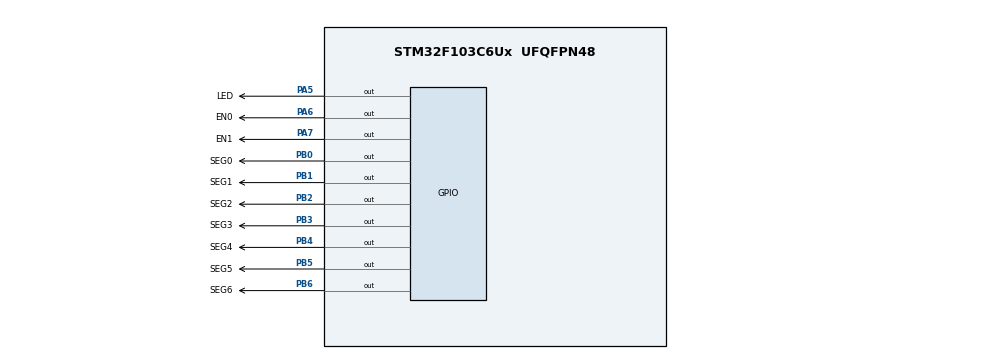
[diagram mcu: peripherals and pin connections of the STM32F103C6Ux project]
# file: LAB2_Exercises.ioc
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Mcu.Family=STM32F1
Mcu.Name=STM32F103C6Ux
Mcu.Package=UFQFPN48
NVIC.PriorityGroup=NVIC_PRIORITYGROUP_4
NVIC.TIM2_IRQn=true\:0\:0\:false\:false\:true\:true\:true
PA5.GPIO_Label=LED
PA5.Signal=GPIO_Output
PA6.GPIO_Label=EN0
PA6.Signal=GPIO_Output
PA7.GPIO_Label=EN1
PA7.Signal=GPIO_Output
PB0.GPIO_Label=SEG0
PB0.Signal=GPIO_Output
PB1.GPIO_Label=SEG1
PB1.Signal=GPIO_Output
PB2.GPIO_Label=SEG2
PB2.Signal=GPIO_Output
PB3.GPIO_Label=SEG3
PB3.Signal=GPIO_Output
PB4.GPIO_Label=SEG4
PB4.Signal=GPIO_Output
PB5.GPIO_Label=SEG5
PB5.Signal=GPIO_Output
PB6.GPIO_Label=SEG6
PB6.Signal=GPIO_Output
ProjectManager.HeapSize=0x200
ProjectManager.StackSize=0x400
ProjectManager.TargetToolchain=STM32CubeIDE
RCC.APB1Freq_Value=8000000
RCC.APB2Freq_Value=8000000
TIM2.Period=9
TIM2.Prescaler=7999
VP_SYS_VS_ND.Mode=No_Debug
VP_TIM2_VS_ClockSourceINT.Mode=Internal
board=custom

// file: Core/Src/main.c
	/* USER CODE BEGIN Header */
/**
  ******************************************************************************
  * @file           : main.c
  * @brief          : Main program body
  ******************************************************************************
  * @attention
  *
  * <h2><center>&copy; Copyright (c) 2023 STMicroelectronics.
  * All rights reserved.</center></h2>
  *
  * This software component is licensed by ST under BSD 3-Clause license,
  * the "License"; You may not use this file except in compliance with the
  * License. You may obtain a copy of the License at:
  *                        opensource.org/licenses/BSD-3-Clause
  *
  ******************************************************************************
  */
/* USER CODE END Header */
#include "main.h"
// Idea : Split the hexadecimal number into corresponding bits for display
void displayDOT ( uint8_t num ) {
	HAL_GPIO_WritePin(ENM0_GPIO_Port, ENM7_Pin, !( num & 0x01 ));
	HAL_GPIO_WritePin(ENM1_GPIO_Port, ENM6_Pin, !( num & 0x02 ));
	HAL_GPIO_WritePin(ENM2_GPIO_Port, ENM5_Pin, !( num & 0x04 ));
	HAL_GPIO_WritePin(ENM3_GPIO_Port, ENM4_Pin, !( num & 0x08 ));
	HAL_GPIO_WritePin(ENM4_GPIO_Port, ENM3_Pin, !( num & 0x10 ));
	HAL_GPIO_WritePin(ENM5_GPIO_Port, ENM2_Pin, !( num & 0x20 ));
	HAL_GPIO_WritePin(ENM6_GPIO_Port, ENM1_Pin, !( num & 0x40 ));
	HAL_GPIO_WritePin(ENM7_GPIO_Port, ENM0_Pin, !( num & 0x80 ));
}

// Idea : For the first time running , turn off all the LEDs for easy display
void clearMatrix () {
	HAL_GPIO_WritePin(ROW0_GPIO_Port, ROW0_Pin, 1);
	HAL_GPIO_WritePin(ROW1_GPIO_Port, ROW1_Pin, 1);
	HAL_GPIO_WritePin(ROW2_GPIO_Port, ROW2_Pin, 1);
	HAL_GPIO_WritePin(ROW3_GPIO_Port, ROW3_Pin, 1);
	HAL_GPIO_WritePin(ROW4_GPIO_Port, ROW4_Pin, 1);
	HAL_GPIO_WritePin(ROW5_GPIO_Port, ROW5_Pin, 1);
	HAL_GPIO_WritePin(ROW6_GPIO_Port, ROW6_Pin, 1);
	HAL_GPIO_WritePin(ROW7_GPIO_Port, ROW7_Pin, 1);
}

// Idea : Display the hexadecimal values in the corresponding row using led scanning
uint8_t matrix_buffer[8] = {0x18, 0x3c, 0x66, 0x7e, 0x66, 0x66, 0x66}; // Character A
void updateLEDMatrix (int index) {
	switch (index) {
	case 0:
		displayDOT(matrix_buffer[0]);
		HAL_GPIO_WritePin(ROW7_GPIO_Port, ROW7_Pin, 1);
		HAL_GPIO_WritePin(ROW0_GPIO_Port, ROW0_Pin, 0);
		break;
	case 1:
		displayDOT(matrix_buffer[1]);
		HAL_GPIO_WritePin(ROW0_GPIO_Port, ROW0_Pin, 1);
		HAL_GPIO_WritePin(ROW1_GPIO_Port, ROW1_Pin, 0);
		break;
	case 2:
		displayDOT(matrix_buffer[2]);
		HAL_GPIO_WritePin(ROW1_GPIO_Port, ROW1_Pin, 1);
		HAL_GPIO_WritePin(ROW2_GPIO_Port, ROW2_Pin, 0);
		break;
	case 3:
		displayDOT(matrix_buffer[3]);
		HAL_GPIO_WritePin(ROW2_GPIO_Port, ROW2_Pin, 1);
		HAL_GPIO_WritePin(ROW3_GPIO_Port, ROW3_Pin, 0);
		break;
	case 4:
		displayDOT(matrix_buffer[4]);
		HAL_GPIO_WritePin(ROW3_GPIO_Port, ROW3_Pin, 1);
		HAL_GPIO_WritePin(ROW4_GPIO_Port, ROW4_Pin, 0);
		break;
	case 5:
		displayDOT(matrix_buffer[5]);
		HAL_GPIO_WritePin(ROW4_GPIO_Port, ROW4_Pin, 1);
		HAL_GPIO_WritePin(ROW5_GPIO_Port, ROW5_Pin, 0);
		break;
	case 6:
		displayDOT(matrix_buffer[6]);
		HAL_GPIO_WritePin(ROW5_GPIO_Port, ROW5_Pin, 1);
		HAL_GPIO_WritePin(ROW6_GPIO_Port, ROW6_Pin, 0);
		break;
	case 7:
		displayDOT(matrix_buffer[7]);
		HAL_GPIO_WritePin(ROW6_GPIO_Port, ROW6_Pin, 1);
		HAL_GPIO_WritePin(ROW7_GPIO_Port, ROW7_Pin, 0);
		break;
	default:
		break;
	}
}

TIM_HandleTypeDef htim2;

void SystemClock_Config(void);
static void MX_GPIO_Init(void);
static void MX_TIM2_Init(void);

/* USER CODE BEGIN 0 */
// Idea: Use another software timer called timer1 for presenting 4  7-SEG LEDs.
// Use  setTimer1(250) and TIMER_CYCLE = 10, we have the timer1_counter = 25, therefore, the switching time between 7-SEG LEDS is 0.25s
int timer2_counter = 0;
int timer2_flag = 0;
int TIMER_CYCLE = 10;
void setTimer2 (int duration) {
	timer2_counter = duration / TIMER_CYCLE;
	timer2_flag = 0;
}
void timer_run () {
	if (timer2_counter > 0) {
		timer2_counter--;
		if (timer2_counter == 0) timer2_flag = 1;
	}
}
/* USER CODE END 0 */

int main(void)
{

  /* MCU Configuration--------------------------------------------------------*/

  /* Reset of all peripherals, Initializes the Flash interface and the Systick. */
  HAL_Init();

  /* Configure the system clock */
  SystemClock_Config();

  /* Initialize all configured peripherals */
  MX_GPIO_Init();
  MX_TIM2_Init();
  /* USER CODE BEGIN 2 */
  HAL_TIM_Base_Start_IT(&htim2);
  /* USER CODE END 2 */

  /* Infinite loop */
  /* USER CODE BEGIN WHILE */
  setTimer2(10);
  int index = 0;
  clearMatrix();
  while (1)
  {
	  if (timer2_flag == 1) {
		  setTimer2(40);
		  updateLEDMatrix(index++);
		  if (index > 7) {
			  index = 0;
		  }
	  }
  }
  /* USER CODE END 3 */
}

void SystemClock_Config(void)
{
  RCC_OscInitTypeDef RCC_OscInitStruct = {0};
  RCC_ClkInitTypeDef RCC_ClkInitStruct = {0};

  /** Initializes the RCC Oscillators according to the specified parameters
  * in the RCC_OscInitTypeDef structure.
  */
  RCC_OscInitStruct.OscillatorType = RCC_OSCILLATORTYPE_HSI;
  RCC_OscInitStruct.HSIState = RCC_HSI_ON;
  RCC_OscInitStruct.HSICalibrationValue = RCC_HSICALIBRATION_DEFAULT;
  RCC_OscInitStruct.PLL.PLLState = RCC_PLL_NONE;
  if (HAL_RCC_OscConfig(&RCC_OscInitStruct) != HAL_OK)
  {
    Error_Handler();
  }
  /** Initializes the CPU, AHB and APB buses clocks
  */
  RCC_ClkInitStruct.ClockType = RCC_CLOCKTYPE_HCLK|RCC_CLOCKTYPE_SYSCLK
                              |RCC_CLOCKTYPE_PCLK1|RCC_CLOCKTYPE_PCLK2;
  RCC_ClkInitStruct.SYSCLKSource = RCC_SYSCLKSOURCE_HSI;
  RCC_ClkInitStruct.AHBCLKDivider = RCC_SYSCLK_DIV1;
  RCC_ClkInitStruct.APB1CLKDivider = RCC_HCLK_DIV1;
  RCC_ClkInitStruct.APB2CLKDivider = RCC_HCLK_DIV1;

  if (HAL_RCC_ClockConfig(&RCC_ClkInitStruct, FLASH_LATENCY_0) != HAL_OK)
  {
    Error_Handler();
  }
}

static void MX_TIM2_Init(void)
{

  TIM_ClockConfigTypeDef sClockSourceConfig = {0};
  TIM_MasterConfigTypeDef sMasterConfig = {0};

  htim2.Instance = TIM2;
  htim2.Init.Prescaler = 7999;
  htim2.Init.CounterMode = TIM_COUNTERMODE_UP;
  htim2.Init.Period = 9;
  htim2.Init.ClockDivision = TIM_CLOCKDIVISION_DIV1;
  htim2.Init.AutoReloadPreload = TIM_AUTORELOAD_PRELOAD_DISABLE;
  if (HAL_TIM_Base_Init(&htim2) != HAL_OK)
  {
    Error_Handler();
  }
  sClockSourceConfig.ClockSource = TIM_CLOCKSOURCE_INTERNAL;
  if (HAL_TIM_ConfigClockSource(&htim2, &sClockSourceConfig) != HAL_OK)
  {
    Error_Handler();
  }
  sMasterConfig.MasterOutputTrigger = TIM_TRGO_RESET;
  sMasterConfig.MasterSlaveMode = TIM_MASTERSLAVEMODE_DISABLE;
  if (HAL_TIMEx_MasterConfigSynchronization(&htim2, &sMasterConfig) != HAL_OK)
  {
    Error_Handler();
  }

}

static void MX_GPIO_Init(void)
{
  GPIO_InitTypeDef GPIO_InitStruct = {0};

  /* GPIO Ports Clock Enable */
  __HAL_RCC_GPIOA_CLK_ENABLE();
  __HAL_RCC_GPIOB_CLK_ENABLE();

  /*Configure GPIO pin Output Level */
  HAL_GPIO_WritePin(GPIOA, ENM0_Pin|ENM1_Pin|DOT_Pin|LED_Pin
                          |EN0_Pin|EN1_Pin|EN2_Pin|EN3_Pin
                          |ENM2_Pin|ENM3_Pin|ENM4_Pin|ENM5_Pin
                          |ENM6_Pin|ENM7_Pin, GPIO_PIN_RESET);

  /*Configure GPIO pin Output Level */
  HAL_GPIO_WritePin(GPIOB, SEG0_Pin|SEG1_Pin|SEG2_Pin|ROW2_Pin
                          |ROW3_Pin|ROW4_Pin|ROW5_Pin|ROW6_Pin
                          |ROW7_Pin|SEG3_Pin|SEG4_Pin|SEG5_Pin
                          |SEG6_Pin|ROW0_Pin|ROW1_Pin, GPIO_PIN_RESET);

  /*Configure GPIO pins : ENM0_Pin ENM1_Pin DOT_Pin LED_Pin
                           EN0_Pin EN1_Pin EN2_Pin EN3_Pin
                           ENM2_Pin ENM3_Pin ENM4_Pin ENM5_Pin
                           ENM6_Pin ENM7_Pin */
  GPIO_InitStruct.Pin = ENM0_Pin|ENM1_Pin|DOT_Pin|LED_Pin
                          |EN0_Pin|EN1_Pin|EN2_Pin|EN3_Pin
                          |ENM2_Pin|ENM3_Pin|ENM4_Pin|ENM5_Pin
                          |ENM6_Pin|ENM7_Pin;
  GPIO_InitStruct.Mode = GPIO_MODE_OUTPUT_PP;
  GPIO_InitStruct.Pull = GPIO_NOPULL;
  GPIO_InitStruct.Speed = GPIO_SPEED_FREQ_LOW;
  HAL_GPIO_Init(GPIOA, &GPIO_InitStruct);

  /*Configure GPIO pins : SEG0_Pin SEG1_Pin SEG2_Pin ROW2_Pin
                           ROW3_Pin ROW4_Pin ROW5_Pin ROW6_Pin
                           ROW7_Pin SEG3_Pin SEG4_Pin SEG5_Pin
                           SEG6_Pin ROW0_Pin ROW1_Pin */
  GPIO_InitStruct.Pin = SEG0_Pin|SEG1_Pin|SEG2_Pin|ROW2_Pin
                          |ROW3_Pin|ROW4_Pin|ROW5_Pin|ROW6_Pin
                          |ROW7_Pin|SEG3_Pin|SEG4_Pin|SEG5_Pin
                          |SEG6_Pin|ROW0_Pin|ROW1_Pin;
  GPIO_InitStruct.Mode = GPIO_MODE_OUTPUT_PP;
  GPIO_InitStruct.Pull = GPIO_NOPULL;
  GPIO_InitStruct.Speed = GPIO_SPEED_FREQ_LOW;
  HAL_GPIO_Init(GPIOB, &GPIO_InitStruct);

}

/* USER CODE BEGIN 4 */
void HAL_TIM_PeriodElapsedCallback(TIM_HandleTypeDef *htim)
{
	timer_run();
}
/* USER CODE END 4 */

void Error_Handler(void)
{
  __disable_irq();
  while (1)
  {
  }
}

/************************ (C) COPYRIGHT STMicroelectronics *****END OF FILE****/
